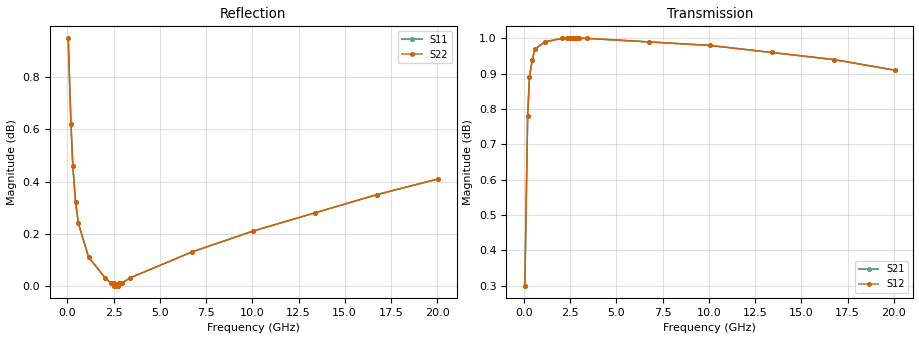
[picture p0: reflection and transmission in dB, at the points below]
! AVX Thin Film Operation		Date: may 2004
! Description: Accu-P® Series, Thin Film, SMD, RF Capacitor
! Part Number: 0201ZK100JBW
! 50 MHz  -  10.05 GHz
! Serial Measurements
# mhz S db R 50
!	S11		S21		S12		S22
!	dB	Phase	dB	Phase	dB	Phase	dB	Phase
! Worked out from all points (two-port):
!   401 points, 50 MHz to 20.05 GHz, reference 50 ohm
!   highest |S21| = 1.00 dB at 2.05 GHz (marker M1); lowest = 0.3 dB at 50 MHz (marker M2)
!   |S21| within 3 dB of the highest: start of sweep to end of sweep
!   lowest |S11| = 0.0 dB at 2.65 GHz (marker M3)
!   |S11| at or under -10 dB: nowhere
!   |S22| runs from 0.0 to 1.0 dB; largest |S21 - S12| = 0
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50  0.95 -17.4  0.30 72.5  0.30 72.5  0.95 -17.4
200  0.62 -51.6  0.78 38.3  0.78 38.3  0.62 -51.6
300  0.46 -62.2  0.89 27.6  0.89 27.6  0.46 -62.2
450  0.32 -70.8  0.94 18.9  0.94 18.9  0.32 -70.8
600  0.24 -75.5  0.97 14.1  0.97 14.1  0.24 -75.5
1150  0.11 -82.8  0.99 6.4  0.99 6.4  0.11 -82.8
2050  0.03 -85.4  1.00 1.8  1.00 1.8  0.03 -85.4
2350  0.01 -83.1  1.00 0.8  1.00 0.8  0.01 -83.1
2450  0.01 -80.2  1.00 0.5  1.00 0.5  0.01 -80.2
2500  0.01 -77.3  1.00 0.4  1.00 0.4  0.01 -77.3
2550  0.00 -71.6  1.00 0.3  1.00 0.3  0.00 -71.6
2650  0.00 -4.3  1.00 0.0  1.00 0.0  0.00 -4.3
2750  0.00 70.1  1.00 -0.2  1.00 -0.2  0.00 70.1
2800  0.01 76.2  1.00 -0.4  1.00 -0.4  0.01 76.2
2850  0.01 79.3  1.00 -0.5  1.00 -0.5  0.01 79.3
2950  0.01 82.4  1.00 -0.7  1.00 -0.7  0.01 82.4
3400  0.03 85.3  1.00 -1.7  1.00 -1.7  0.03 85.3
6750  0.13 82.0  0.99 -7.3  0.99 -7.3  0.13 82.0
10050  0.21 77.7  0.98 -11.9  0.98 -11.9  0.21 77.7
13400  0.28 73.5  0.96 -16.2  0.96 -16.2  0.28 73.5
16750  0.35 69.5  0.94 -20.2  0.94 -20.2  0.35 69.5
20050  0.41 65.8  0.91 -24.0  0.91 -24.0  0.41 65.8
